VERSION 5.7 ;
  NOWIREEXTENSIONATPIN ON ;
  DIVIDERCHAR "/" ;
  BUSBITCHARS "[]" ;
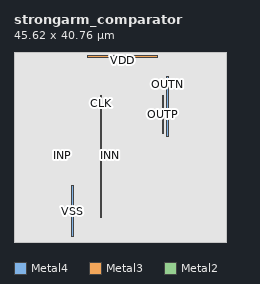
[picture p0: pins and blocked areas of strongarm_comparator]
MACRO strongarm_comparator
  CLASS BLOCK ;
  FOREIGN strongarm_comparator ;
  ORIGIN 22.920 3.940 ;
  SIZE 45.620 BY 40.760 ;
  PIN OUTN
    ANTENNAGATEAREA 6.000000 ;
    ANTENNADIFFAREA 5.840000 ;
    PORT
      LAYER Metal4 ;
        RECT 9.860 18.620 10.140 31.600 ;
    END
  END OUTN
  PIN OUTP
    ANTENNAGATEAREA 6.000000 ;
    ANTENNADIFFAREA 5.840000 ;
    PORT
      LAYER Metal3 ;
        RECT 8.840 19.360 9.120 27.520 ;
    END
  END OUTP
  PIN CLK
    ANTENNAGATEAREA 8.000000 ;
    PORT
      LAYER Metal4 ;
        RECT -4.420 1.280 -4.140 27.520 ;
    END
  END CLK
  PIN INN
    ANTENNAGATEAREA 6.000000 ;
    PORT
      LAYER Metal2 ;
        RECT -2.570 14.550 -2.290 14.830 ;
    END
  END INN
  PIN INP
    ANTENNAGATEAREA 6.000000 ;
    PORT
      LAYER Metal2 ;
        RECT -12.670 14.550 -12.390 14.830 ;
    END
  END INP
  PIN VSS
    USE GROUND ;
    PORT
      LAYER Metal4 ;
        RECT -10.680 -2.800 -10.120 8.140 ;
    END
  END VSS
  PIN VDD
    USE POWER ;
    PORT
      LAYER Metal3 ;
        RECT -7.200 35.540 7.820 36.100 ;
    END
  END VDD
  OBS
      LAYER Nwell ;
        RECT -19.700 0.000 19.700 33.270 ;
      LAYER Metal1 ;
        RECT -19.470 0.210 19.470 33.060 ;
      LAYER Metal2 ;
        RECT -19.830 15.130 19.470 33.060 ;
        RECT -19.830 14.250 -12.970 15.130 ;
        RECT -12.090 14.250 -2.870 15.130 ;
        RECT -1.990 14.250 19.470 15.130 ;
        RECT -19.830 0.210 19.470 14.250 ;
      LAYER Metal3 ;
        RECT -22.920 35.240 -7.500 36.100 ;
        RECT 8.120 35.240 22.520 36.100 ;
        RECT -22.920 27.820 22.520 35.240 ;
        RECT -22.920 19.060 8.540 27.820 ;
        RECT 9.420 19.060 22.520 27.820 ;
        RECT -22.920 -3.220 22.520 19.060 ;
      LAYER Metal4 ;
        RECT -22.890 31.900 22.490 36.070 ;
        RECT -22.890 27.820 9.560 31.900 ;
        RECT -22.890 8.440 -4.720 27.820 ;
        RECT -22.890 -3.100 -10.980 8.440 ;
        RECT -9.820 0.980 -4.720 8.440 ;
        RECT -3.840 18.320 9.560 27.820 ;
        RECT 10.440 18.320 22.490 31.900 ;
        RECT -3.840 0.980 22.490 18.320 ;
        RECT -9.820 -3.100 22.490 0.980 ;
        RECT -22.890 -3.220 22.490 -3.100 ;
      LAYER Metal5 ;
        RECT -22.890 -3.940 22.700 36.820 ;
  END
END strongarm_comparator
END LIBRARY

